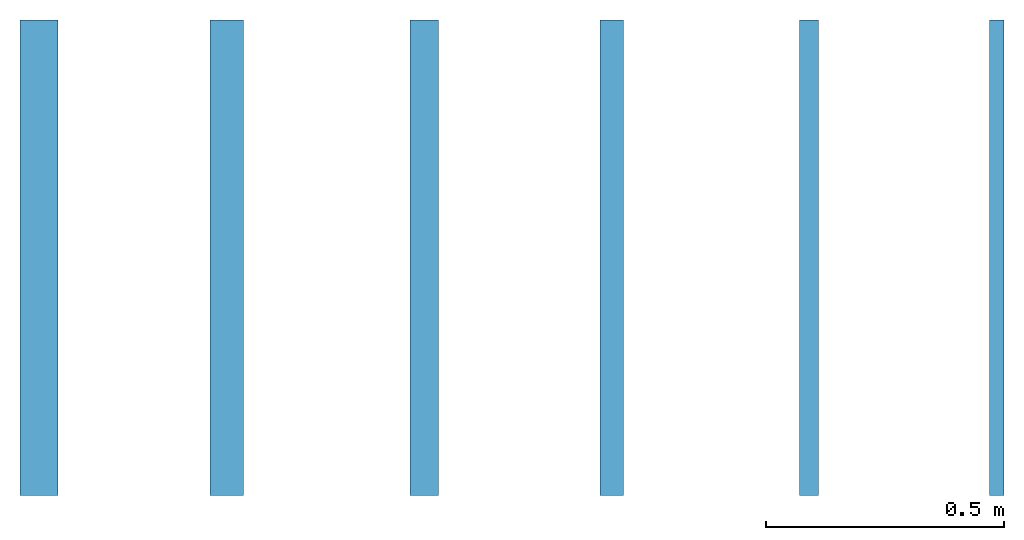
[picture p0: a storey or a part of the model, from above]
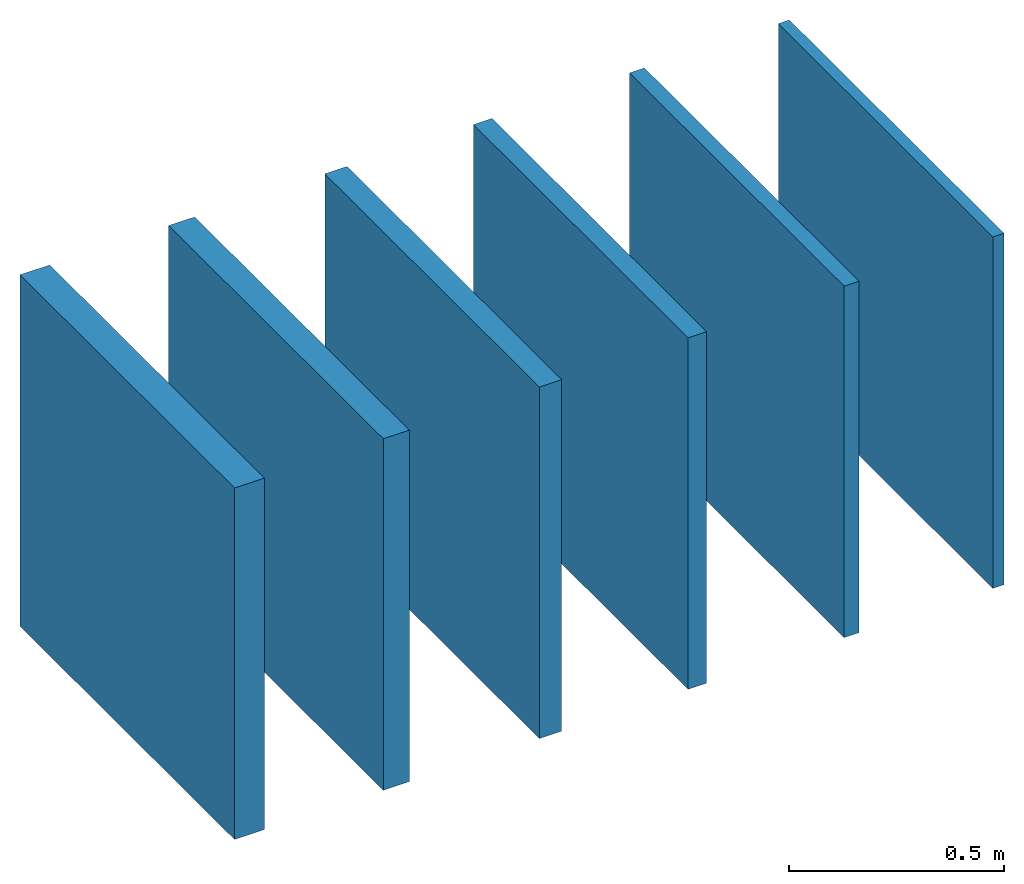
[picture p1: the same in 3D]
Properties of the parts of a building model (IFC2X3)

# File
Description: ViewDefinition [CoordinationView_V2.0]
File name: 0001
Time: 2017-06-13T10:07:13
Written by: The EXPRESS Data Manager Version 5.02.0100.07 : 28 Aug 2013
Made in: 20170223_1515(x64) - Exporter 18.0.0.420 - Alternate UI 18.0.0.420
Comment: STEP Physical File produced by: The EXPRESS Data Manager Version 5.02.0100.07 : 28 Aug 2013 * Module: EDMstepFileFactory/EDMstandAlone * Creation date: Tue Jun 13 10:07:13 2017 * Host: JAVIER * Database: C:\Users\JAVIER~1.DOM\AppData\Local\Temp\{84DDB97F-FCAF-45D9-A33C-D307F7C2D07D}\ifc * Database version: 5507 * Database creation date: Tue Jun 13 10:07:13 2017 * Schema: IFC2X3 * Model: DataRepository.ifc * Model creation date: Tue Jun 13 10:07:13 2017 * Header model: DataRepository.ifc_HeaderModel * Header model creation date: Tue Jun 13 10:07:13 2017 * EDMuser: sdai-user * EDMgroup: sdai-group * License ID and type: 5605 : Permanent license. Expiry date: * EDMstepFileFactory options: 020000

# IfcProject, 0001
LongName: Nombre de proyecto; Phase: Estado de proyecto

# IfcSite, Default
RefLatitude: 40, 24, 0, 5493; RefLongitude: -3, -40, -59, -880065; RefElevation: 0 m

# IfcBuilding
Pset_BuildingCommon - NumberOfStoreys: 1

# IfcBuildingStorey, Nivel 1
LongName: Nivel 1; Elevation: 0 m

# IfcWallStandardCase: Muro básico:Grafipol TR-0_1000x1000x30mm, Muro básico:Grafipol TR-0_1000x1000x30mm:166242
In: Nivel 1
Type - PredefinedType: STANDARD; Material: VALERO Grafipol® TR-0 0.03 m
Pset_WallCommon - LoadBearing: no; ExtendToStructure: no; IsExternal: no; Reference: Grafipol TR-0_1000x1000x30mm; FireRating: E; ThermalTransmittance: 1.1 kg/K/s3
Pset_ManufacturerTypeInformation - Manufacturer: Grupo Valero - José Manuel Valero, S. L.

# IfcWallStandardCase: Muro básico:Grafipol TR-0_1000x1000x40mm, Muro básico:Grafipol TR-0_1000x1000x40mm:165146
In: Nivel 1
Type - PredefinedType: STANDARD; Material: VALERO Grafipol® TR-0 0.04 m
Pset_WallCommon - Reference: Grafipol TR-0_1000x1000x40mm; LoadBearing: no; ExtendToStructure: no; IsExternal: no; FireRating: E; ThermalTransmittance: 0.825 kg/K/s3
Pset_ManufacturerTypeInformation - Manufacturer: Grupo Valero - José Manuel Valero, S. L.

# IfcWallStandardCase: Muro básico:Grafipol TR-0_1000x1000x50mm, Muro básico:Grafipol TR-0_1000x1000x50mm:166297
In: Nivel 1
Type - PredefinedType: STANDARD; Material: VALERO Grafipol® TR-0 0.05 m
Pset_WallCommon - LoadBearing: no; ExtendToStructure: no; IsExternal: no; Reference: Grafipol TR-0_1000x1000x50mm; FireRating: E; ThermalTransmittance: 0.66 kg/K/s3
Pset_ManufacturerTypeInformation - Manufacturer: Grupo Valero - José Manuel Valero, S. L.

# IfcWallStandardCase: Muro básico:Grafipol TR-0_1000x1000x60mm, Muro básico:Grafipol TR-0_1000x1000x60mm:166296
In: Nivel 1
Type - PredefinedType: STANDARD; Material: VALERO Grafipol® TR-0 0.06 m
Pset_WallCommon - LoadBearing: no; ExtendToStructure: no; IsExternal: no; Reference: Grafipol TR-0_1000x1000x60mm; FireRating: E; ThermalTransmittance: 0.55 kg/K/s3
Pset_ManufacturerTypeInformation - Manufacturer: Grupo Valero - José Manuel Valero, S. L.

# IfcWallStandardCase: Muro básico:Grafipol TR-0_1000x1000x70mm, Muro básico:Grafipol TR-0_1000x1000x70mm:166317
In: Nivel 1
Type - PredefinedType: STANDARD; Material: VALERO Grafipol® TR-0 0.07 m
Pset_WallCommon - LoadBearing: no; ExtendToStructure: no; IsExternal: no; Reference: Grafipol TR-0_1000x1000x70mm; FireRating: E; ThermalTransmittance: 0.471429 kg/K/s3
Pset_ManufacturerTypeInformation - Manufacturer: Grupo Valero - José Manuel Valero, S. L.

# IfcWallStandardCase: Muro básico:Grafipol TR-0_1000x1000x80mm, Muro básico:Grafipol TR-0_1000x1000x80mm:166316
In: Nivel 1
Type - PredefinedType: STANDARD; Material: VALERO Grafipol® TR-0 0.08 m
Pset_WallCommon - LoadBearing: no; ExtendToStructure: no; IsExternal: no; Reference: Grafipol TR-0_1000x1000x80mm; FireRating: E; ThermalTransmittance: 0.4125 kg/K/s3
Pset_ManufacturerTypeInformation - Manufacturer: Grupo Valero - José Manuel Valero, S. L.
